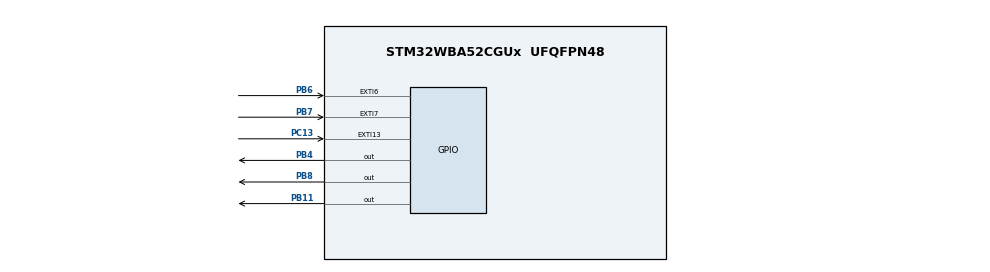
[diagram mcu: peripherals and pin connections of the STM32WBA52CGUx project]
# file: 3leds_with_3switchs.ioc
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CORTEX_M33_NS.userName=CORTEX_M33
Mcu.Family=STM32WBA
Mcu.Name=STM32WBA52CGUx
Mcu.Package=UFQFPN48
NUCLEO-WBA52CG.BUTTON=1
NUCLEO-WBA52CG.BUTTON2=1
NUCLEO-WBA52CG.BUTTON3=1
NUCLEO-WBA52CG.LD1=true
NUCLEO-WBA52CG.LD2=true
NUCLEO-WBA52CG.LD3=true
NUCLEO-WBA52CG.VCP=true
NVIC.EXTI13_IRQn=true\:0\:0\:false\:false\:true\:true\:true\:true
NVIC.EXTI6_IRQn=true\:0\:0\:false\:false\:true\:true\:true\:true
NVIC.EXTI7_IRQn=true\:0\:0\:false\:false\:true\:true\:true\:true
NVIC.PriorityGroup=NVIC_PRIORITYGROUP_4
OSC_IN.GPIO_Label=RCC_OSC_IN
OSC_IN.Signal=RCC_OSC_IN
OSC_OUT.GPIO_Label=RCC_OSC_OUT
OSC_OUT.Signal=RCC_OSC_OUT
PA13\ (JTMS/SWDIO).GPIO_Label=DEBUG_JTMS-SWDIO
PA13\ (JTMS/SWDIO).Signal=DEBUG_JTMS-SWDIO
PA14\ (JTCK/SWCLK).GPIO_Label=DEBUG_JTCK-SWCLK
PA14\ (JTCK/SWCLK).Signal=DEBUG_JTCK-SWCLK
PA8.Signal=USART1_RX
PB11.Signal=GPIO_Output
PB12.Signal=USART1_TX
PB4\ (NJTRST).Signal=GPIO_Output
PB6.Signal=GPXTI6
PB7.Signal=GPXTI7
PB8.Signal=GPIO_Output
PC13.Signal=GPXTI13
PC14-OSC32_IN.GPIO_Label=RCC_OSC32_IN
PC14-OSC32_IN.Signal=RCC_OSC32_IN
PC15-OSC32_OUT.GPIO_Label=RCC_OSC32_OUT
PC15-OSC32_OUT.Signal=RCC_OSC32_OUT
ProjectManager.HeapSize=0x200
ProjectManager.StackSize=0x400
ProjectManager.TargetToolchain=STM32CubeIDE
RCC.ADCFreq_Value=16000000
RCC.AHBFreq_Value=16000000
RCC.APB1Freq_Value=16000000
RCC.APB1TimFreq_Value=16000000
RCC.APB2Freq_Value=16000000
RCC.APB2TimFreq_Value=16000000
RCC.CortexFreq_Value=2000000
RCC.HCLKFreq_Value=16000000
RCC.HSE_VALUE=32000000
RCC.HSI_VALUE=16000000
RCC.LSE_VALUE=32768
RCC.PWR_Regulator_Voltage_Scale=PWR_REGULATOR_VOLTAGE_SCALE1
RCC.SYSCLKFreq_VALUE=16000000
RCC.VCOOutputFreq_Value=2064000000
VP_CORTEX_M33_NS_VS_Hclk.Mode=Hclk_Mode
VP_ICACHE_VS_ICACHE.Mode=DirectMappedCache
VP_MEMORYMAP_VS_MEMORYMAP.Mode=CurAppReg
VP_NUCLEO-WBA52CG_VS_BSP_COMMON.Mode=COMMON
VP_PWR_VS_SECSignals.Mode=Security/Privilege
board=NUCLEO-WBA52CG

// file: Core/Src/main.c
/* USER CODE BEGIN Header */
/**
  ******************************************************************************
  * @file           : main.c
  * @brief          : Main program body
  ******************************************************************************
  * @attention
  *
  * Copyright (c) 2024 STMicroelectronics.
  * All rights reserved.
  *
  * This software is licensed under terms that can be found in the LICENSE file
  * in the root directory of this software component.
  * If no LICENSE file comes with this software, it is provided AS-IS.
  *
  ******************************************************************************
  */
/* USER CODE END Header */
#include "main.h"

COM_InitTypeDef BspCOMInit;

void SystemClock_Config(void);
static void MX_GPIO_Init(void);
static void MX_ICACHE_Init(void);

int main(void)
{

  /* MCU Configuration--------------------------------------------------------*/

  /* Reset of all peripherals, Initializes the Flash interface and the Systick. */
  HAL_Init();

  /* Configure the system clock */
  SystemClock_Config();

  /* Initialize all configured peripherals */
  MX_GPIO_Init();
  MX_ICACHE_Init();

  /* Initialize leds */
  BSP_LED_Init(LED_BLUE);
  BSP_LED_Init(LED_GREEN);
  BSP_LED_Init(LED_RED);

  /* Initialize USER push-button, will be used to trigger an interrupt each time it's pressed.*/
  BSP_PB_Init(B1, BUTTON_MODE_EXTI);
  BSP_PB_Init(B2, BUTTON_MODE_EXTI);
  BSP_PB_Init(B3, BUTTON_MODE_EXTI);

  /* Initialize COM1 port (115200, 8 bits (7-bit data + 1 stop bit), no parity */
  BspCOMInit.BaudRate   = 115200;
  BspCOMInit.WordLength = COM_WORDLENGTH_8B;
  BspCOMInit.StopBits   = COM_STOPBITS_1;
  BspCOMInit.Parity     = COM_PARITY_NONE;
  BspCOMInit.HwFlowCtl  = COM_HWCONTROL_NONE;
  if (BSP_COM_Init(COM1, &BspCOMInit) != BSP_ERROR_NONE)
  {
    Error_Handler();
  }

  /* Infinite loop */
  while (1)
  {
	  if(HAL_GPIO_ReadPin(B1_GPIO_PORT, B1_PIN)==GPIO_PIN_RESET){

		HAL_Delay(250);
	  	HAL_GPIO_TogglePin(LD1_GPIO_PORT, LD1_PIN);
	  }
	  else if(HAL_GPIO_ReadPin(B2_GPIO_PORT, B2_PIN)==GPIO_PIN_RESET){

	  		HAL_Delay(250);
	  	  	HAL_GPIO_TogglePin(LD2_GPIO_PORT, LD2_PIN);
	  	  }
	  else if(HAL_GPIO_ReadPin(B3_GPIO_PORT, B3_PIN)==GPIO_PIN_RESET){

	  	  		HAL_Delay(250);
	  	  	  	HAL_GPIO_TogglePin(LD3_GPIO_PORT, LD3_PIN);
	  	  	  }
  }
}

void SystemClock_Config(void)
{
  RCC_OscInitTypeDef RCC_OscInitStruct = {0};
  RCC_ClkInitTypeDef RCC_ClkInitStruct = {0};

  /** Configure the main internal regulator output voltage
  */
  if (HAL_PWREx_ControlVoltageScaling(PWR_REGULATOR_VOLTAGE_SCALE1) != HAL_OK)
  {
    Error_Handler();
  }

  /** Initializes the CPU, AHB and APB busses clocks
  */
  RCC_OscInitStruct.OscillatorType = RCC_OSCILLATORTYPE_HSI;
  RCC_OscInitStruct.HSIState = RCC_HSI_ON;
  RCC_OscInitStruct.HSICalibrationValue = RCC_HSICALIBRATION_DEFAULT;
  RCC_OscInitStruct.PLL1.PLLState = RCC_PLL_ON;
  RCC_OscInitStruct.PLL1.PLLSource = RCC_PLLSOURCE_HSI;
  RCC_OscInitStruct.PLL1.PLLM = 1;
  RCC_OscInitStruct.PLL1.PLLN = 8;
  RCC_OscInitStruct.PLL1.PLLP = 2;
  RCC_OscInitStruct.PLL1.PLLQ = 2;
  RCC_OscInitStruct.PLL1.PLLR = 2;
  RCC_OscInitStruct.PLL1.PLLFractional = 0;
  if (HAL_RCC_OscConfig(&RCC_OscInitStruct) != HAL_OK)
  {
    Error_Handler();
  }

  /** Initializes the CPU, AHB and APB busses clocks
  */
  RCC_ClkInitStruct.ClockType = RCC_CLOCKTYPE_HCLK|RCC_CLOCKTYPE_SYSCLK
                              |RCC_CLOCKTYPE_PCLK1|RCC_CLOCKTYPE_PCLK2
                              |RCC_CLOCKTYPE_PCLK7|RCC_CLOCKTYPE_HCLK5;
  RCC_ClkInitStruct.SYSCLKSource = RCC_SYSCLKSOURCE_PLLCLK;
  RCC_ClkInitStruct.AHBCLKDivider = RCC_SYSCLK_DIV1;
  RCC_ClkInitStruct.APB1CLKDivider = RCC_HCLK_DIV1;
  RCC_ClkInitStruct.APB2CLKDivider = RCC_HCLK_DIV1;
  RCC_ClkInitStruct.APB7CLKDivider = RCC_HCLK_DIV1;
  RCC_ClkInitStruct.AHB5_PLL1_CLKDivider = RCC_SYSCLK_PLL1_DIV2;
  RCC_ClkInitStruct.AHB5_HSEHSI_CLKDivider = RCC_SYSCLK_HSEHSI_DIV1;

  if (HAL_RCC_ClockConfig(&RCC_ClkInitStruct, FLASH_LATENCY_1) != HAL_OK)
  {
    Error_Handler();
  }
}

static void MX_ICACHE_Init(void)
{

  /** Enable instruction cache in 1-way (direct mapped cache)
  */
  if (HAL_ICACHE_ConfigAssociativityMode(ICACHE_1WAY) != HAL_OK)
  {
    Error_Handler();
  }
  if (HAL_ICACHE_Enable() != HAL_OK)
  {
    Error_Handler();
  }

}

static void MX_GPIO_Init(void)
{

  /* GPIO Ports Clock Enable */
  __HAL_RCC_GPIOC_CLK_ENABLE();
  __HAL_RCC_GPIOA_CLK_ENABLE();

}

void Error_Handler(void)
{
  __disable_irq();
  while (1)
  {
  }
}
